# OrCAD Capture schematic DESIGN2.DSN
size A

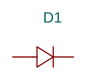
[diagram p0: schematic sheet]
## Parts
D1  Dbreak

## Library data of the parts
D1 = Dbreak

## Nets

Not connected (* = marked no-connect by the designer): D1 0(1) 1(2)
